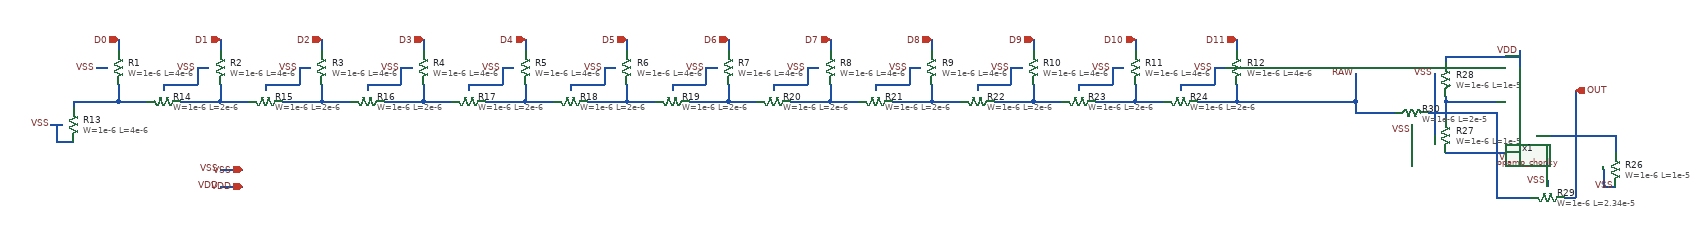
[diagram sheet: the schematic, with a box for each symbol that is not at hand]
v {xschem version=3.4.8RC file_version=1.3}
G {}
K {}
V {}
S {}
F {}
E {}
N -1370 -20 -1350 -20 {lab=VSS}
N -1190 -20 -1170 -20 {lab=VSS}
N -1010 -20 -990 -20 {lab=VSS}
N -830 -20 -810 -20 {lab=VSS}
N -650 -20 -630 -20 {lab=VSS}
N -470 -20 -450 -20 {lab=VSS}
N -290 -20 -270 -20 {lab=VSS}
N -110 -20 -90 -20 {lab=VSS}
N 70 -20 90 -20 {lab=VSS}
N 250 -20 270 -20 {lab=VSS}
N 430 -20 450 -20 {lab=VSS}
N 610 -20 630 -20 {lab=VSS}
N -1330 -70 -1330 -50 {lab=D0}
N -1150 -70 -1150 -50 {lab=D1}
N -970 -70 -970 -50 {lab=D2}
N -790 -70 -790 -50 {lab=D3}
N -610 -70 -610 -50 {lab=D4}
N -430 -70 -430 -50 {lab=D5}
N -250 -70 -250 -50 {lab=D6}
N -70 -70 -70 -50 {lab=D7}
N 110 -70 110 -50 {lab=D8}
N 290 -70 290 -50 {lab=D9}
N 470 -70 470 -50 {lab=D10}
N 650 -70 650 -50 {lab=D11}
N -1450 80 -1430 80 {lab=VSS}
N -1440 110 -1410 110 {lab=VSS}
N -1440 80 -1440 110 {lab=VSS}
N -1250 10 -1250 20 {lab=VSS}
N -1250 10 -1190 10 {lab=VSS}
N -1190 -20 -1190 10 {lab=VSS}
N -1330 10 -1330 40 {lab=#net1}
N -1330 40 -1280 40 {lab=#net1}
N -1220 40 -1150 40 {lab=#net2}
N -1150 10 -1150 40 {lab=#net2}
N -1150 40 -1100 40 {lab=#net2}
N -1040 40 -970 40 {lab=#net3}
N -970 10 -970 40 {lab=#net3}
N -1070 10 -1070 20 {lab=VSS}
N -1070 10 -1010 10 {lab=VSS}
N -1010 -20 -1010 10 {lab=VSS}
N -970 40 -920 40 {lab=#net3}
N -860 40 -790 40 {lab=#net4}
N -790 10 -790 40 {lab=#net4}
N -890 10 -890 20 {lab=VSS}
N -890 10 -830 10 {lab=VSS}
N -830 -20 -830 10 {lab=VSS}
N -1410 40 -1410 50 {lab=#net1}
N -1410 40 -1330 40 {lab=#net1}
N -790 40 -740 40 {lab=#net4}
N -680 40 -610 40 {lab=#net5}
N -610 10 -610 40 {lab=#net5}
N -710 10 -710 20 {lab=VSS}
N -710 10 -650 10 {lab=VSS}
N -650 -20 -650 10 {lab=VSS}
N -610 40 -560 40 {lab=#net5}
N -530 10 -530 20 {lab=VSS}
N -530 10 -470 10 {lab=VSS}
N -470 -20 -470 10 {lab=VSS}
N -500 40 -430 40 {lab=#net6}
N -430 10 -430 40 {lab=#net6}
N -430 40 -380 40 {lab=#net6}
N -320 40 -250 40 {lab=#net7}
N -250 10 -250 40 {lab=#net7}
N -350 10 -350 20 {lab=VSS}
N -350 10 -290 10 {lab=VSS}
N -290 -20 -290 10 {lab=VSS}
N -250 40 -200 40 {lab=#net7}
N -170 10 -170 20 {lab=VSS}
N -170 10 -110 10 {lab=VSS}
N -110 -20 -110 10 {lab=VSS}
N -140 40 -70 40 {lab=#net8}
N -70 10 -70 40 {lab=#net8}
N -70 40 -20 40 {lab=#net8}
N 10 10 10 20 {lab=VSS}
N 10 10 70 10 {lab=VSS}
N 70 -20 70 10 {lab=VSS}
N 40 40 110 40 {lab=#net9}
N 110 10 110 40 {lab=#net9}
N 110 40 160 40 {lab=#net9}
N 190 10 190 20 {lab=VSS}
N 190 10 250 10 {lab=VSS}
N 250 -20 250 10 {lab=VSS}
N 220 40 290 40 {lab=#net10}
N 290 10 290 40 {lab=#net10}
N 290 40 340 40 {lab=#net10}
N 370 10 370 20 {lab=VSS}
N 370 10 430 10 {lab=VSS}
N 430 -20 430 10 {lab=VSS}
N 400 40 470 40 {lab=#net11}
N 470 10 470 40 {lab=#net11}
N 470 40 520 40 {lab=#net11}
N 550 10 550 20 {lab=VSS}
N 550 10 610 10 {lab=VSS}
N 610 -20 610 10 {lab=VSS}
N 580 40 650 40 {lab=RAW}
N 650 10 650 40 {lab=RAW}
N -1150 160 -1110 160 {lab=VSS}
N -1150 190 -1110 190 {lab=VDD}
N 650 40 760 40 {lab=RAW}
N 760 40 820 40 {lab=RAW}
N 860 -10 860 40 {lab=RAW}
N 820 40 860 40 {lab=RAW}
N 1150 -50 1150 -20 {lab=VDD}
N 1150 120 1150 140 {lab=VSS}
N 1250 50 1250 210 {lab=OUT}
N 1180 100 1320 100 {lab=#net12}
N 1320 100 1320 130 {lab=#net12}
N 1300 160 1300 190 {lab=VSS}
N 1300 190 1320 190 {lab=VSS}
N 1250 20 1250 50 {lab=OUT}
N 1020 40 1110 40 {lab=#net13}
N 1020 30 1020 40 {lab=#net13}
N 1020 -40 1020 -30 {lab=VDD}
N 1020 -40 1150 -40 {lab=VDD}
N 1020 40 1020 70 {lab=#net13}
N 1020 130 1150 130 {lab=VSS}
N 1000 -0 1000 100 {lab=VSS}
N 1230 210 1250 210 {lab=OUT}
N 1110 210 1170 210 {lab=#net14}
N 1110 60 1110 210 {lab=#net14}
N 990 60 1110 60 {lab=#net14}
N 860 60 930 60 {lab=RAW}
N 860 40 860 60 {lab=RAW}
N 1200 180 1200 190 {lab=VSS}
N 1000 -10 1000 -0 {lab=VSS}
N 960 80 960 90 {lab=VSS}
C {lab_pin.sym} -1370 -20 0 0 {name=p1 sig_type=std_logic lab=VSS}
C {lab_pin.sym} -1190 -20 0 0 {name=p2 sig_type=std_logic lab=VSS}
C {lab_pin.sym} -1010 -20 0 0 {name=p3 sig_type=std_logic lab=VSS}
C {lab_pin.sym} -830 -20 0 0 {name=p4 sig_type=std_logic lab=VSS}
C {lab_pin.sym} -650 -20 0 0 {name=p5 sig_type=std_logic lab=VSS}
C {lab_pin.sym} -470 -20 0 0 {name=p6 sig_type=std_logic lab=VSS}
C {lab_pin.sym} -290 -20 0 0 {name=p7 sig_type=std_logic lab=VSS}
C {lab_pin.sym} -110 -20 0 0 {name=p8 sig_type=std_logic lab=VSS}
C {lab_pin.sym} 70 -20 0 0 {name=p9 sig_type=std_logic lab=VSS}
C {lab_pin.sym} 250 -20 0 0 {name=p10 sig_type=std_logic lab=VSS}
C {lab_pin.sym} 430 -20 0 0 {name=p11 sig_type=std_logic lab=VSS}
C {lab_pin.sym} 610 -20 0 0 {name=p12 sig_type=std_logic lab=VSS}
C {ipin.sym} -1330 -70 1 0 {name=p13 lab=D0}
C {ipin.sym} -1150 -70 1 0 {name=p14 lab=D1}
C {ipin.sym} -970 -70 1 0 {name=p15 lab=D2}
C {ipin.sym} -790 -70 1 0 {name=p16 lab=D3}
C {ipin.sym} -610 -70 1 0 {name=p17 lab=D4}
C {ipin.sym} -430 -70 1 0 {name=p18 lab=D5}
C {ipin.sym} -250 -70 1 0 {name=p19 lab=D6}
C {ipin.sym} -70 -70 1 0 {name=p20 lab=D7}
C {ipin.sym} 110 -70 1 0 {name=p21 lab=D8}
C {ipin.sym} 290 -70 1 0 {name=p22 lab=D9}
C {ipin.sym} 470 -70 1 0 {name=p23 lab=D10}
C {ipin.sym} 650 -70 1 0 {name=p24 lab=D11}
C {lab_pin.sym} -1450 80 0 0 {name=p25 sig_type=std_logic lab=VSS}
C {lab_pin.sym} -1150 160 0 0 {name=p26 sig_type=std_logic lab=VSS}
C {iopin.sym} -1110 160 0 0 {name=p27 lab=VSS}
C {lab_pin.sym} -1150 190 0 0 {name=p30 sig_type=std_logic lab=VDD}
C {iopin.sym} -1110 190 0 0 {name=p31 lab=VDD}
C {lab_pin.sym} 860 -10 1 0 {name=p28 sig_type=std_logic lab=RAW}
C {lab_pin.sym} 1150 -50 1 0 {name=p29 sig_type=std_logic lab=VDD}
C {lab_pin.sym} 1150 140 3 0 {name=p32 sig_type=std_logic lab=VSS}
C {symbols/npolyf_u.sym} 1320 160 0 0 {name=R26
W=1e-6
L=1e-5
model=ppolyf_u_1k_6p0
spiceprefix=X
m=1}
C {opin.sym} 1250 20 0 0 {name=p33 lab=OUT}
C {symbols/npolyf_u.sym} 1020 100 0 0 {name=R27
W=1e-6
L=1e-5
model=ppolyf_u_1k_6p0
spiceprefix=X
m=1}
C {symbols/npolyf_u.sym} 1020 0 0 0 {name=R28
W=1e-6
L=1e-5
model=ppolyf_u_1k_6p0
spiceprefix=X
m=1}
C {symbols/ppolyf_u_1k_6p0.sym} -1330 -20 0 0 {name=R1
W=1e-6
L=4e-6
model=ppolyf_u_1k_6p0
spiceprefix=X
m=1}
C {symbols/ppolyf_u_1k_6p0.sym} -1150 -20 0 0 {name=R2
W=1e-6
L=4e-6
model=ppolyf_u_1k_6p0
spiceprefix=X
m=1}
C {symbols/ppolyf_u_1k_6p0.sym} -970 -20 0 0 {name=R3
W=1e-6
L=4e-6
model=ppolyf_u_1k_6p0
spiceprefix=X
m=1}
C {symbols/ppolyf_u_1k_6p0.sym} -790 -20 0 0 {name=R4
W=1e-6
L=4e-6
model=ppolyf_u_1k_6p0
spiceprefix=X
m=1}
C {symbols/ppolyf_u_1k_6p0.sym} -610 -20 0 0 {name=R5
W=1e-6
L=4e-6
model=ppolyf_u_1k_6p0
spiceprefix=X
m=1}
C {symbols/ppolyf_u_1k_6p0.sym} -430 -20 0 0 {name=R6
W=1e-6
L=4e-6
model=ppolyf_u_1k_6p0
spiceprefix=X
m=1}
C {symbols/ppolyf_u_1k_6p0.sym} -250 -20 0 0 {name=R7
W=1e-6
L=4e-6
model=ppolyf_u_1k_6p0
spiceprefix=X
m=1}
C {symbols/ppolyf_u_1k_6p0.sym} -70 -20 0 0 {name=R8
W=1e-6
L=4e-6
model=ppolyf_u_1k_6p0
spiceprefix=X
m=1}
C {symbols/ppolyf_u_1k_6p0.sym} 110 -20 0 0 {name=R9
W=1e-6
L=4e-6
model=ppolyf_u_1k_6p0
spiceprefix=X
m=1}
C {symbols/ppolyf_u_1k_6p0.sym} 290 -20 0 0 {name=R10
W=1e-6
L=4e-6
model=ppolyf_u_1k_6p0
spiceprefix=X
m=1}
C {symbols/ppolyf_u_1k_6p0.sym} 470 -20 0 0 {name=R11
W=1e-6
L=4e-6
model=ppolyf_u_1k_6p0
spiceprefix=X
m=1}
C {symbols/ppolyf_u_1k_6p0.sym} 650 -20 0 0 {name=R12
W=1e-6
L=4e-6
model=ppolyf_u_1k_6p0
spiceprefix=X
m=1}
C {symbols/ppolyf_u_1k_6p0.sym} -1410 80 0 0 {name=R13
W=1e-6
L=4e-6
model=ppolyf_u_1k_6p0
spiceprefix=X
m=1}
C {symbols/ppolyf_u_1k_6p0.sym} -1250 40 1 0 {name=R14
W=1e-6
L=2e-6
model=ppolyf_u_1k_6p0
spiceprefix=X
m=1}
C {symbols/ppolyf_u_1k_6p0.sym} -1070 40 1 0 {name=R15
W=1e-6
L=2e-6
model=ppolyf_u_1k_6p0
spiceprefix=X
m=1}
C {symbols/ppolyf_u_1k_6p0.sym} -890 40 1 0 {name=R16
W=1e-6
L=2e-6
model=ppolyf_u_1k_6p0
spiceprefix=X
m=1}
C {symbols/ppolyf_u_1k_6p0.sym} -710 40 1 0 {name=R17
W=1e-6
L=2e-6
model=ppolyf_u_1k_6p0
spiceprefix=X
m=1}
C {symbols/ppolyf_u_1k_6p0.sym} -530 40 1 0 {name=R18
W=1e-6
L=2e-6
model=ppolyf_u_1k_6p0
spiceprefix=X
m=1}
C {symbols/ppolyf_u_1k_6p0.sym} -350 40 1 0 {name=R19
W=1e-6
L=2e-6
model=ppolyf_u_1k_6p0
spiceprefix=X
m=1}
C {symbols/ppolyf_u_1k_6p0.sym} -170 40 1 0 {name=R20
W=1e-6
L=2e-6
model=ppolyf_u_1k_6p0
spiceprefix=X
m=1}
C {symbols/ppolyf_u_1k_6p0.sym} 10 40 1 0 {name=R21
W=1e-6
L=2e-6
model=ppolyf_u_1k_6p0
spiceprefix=X
m=1}
C {symbols/ppolyf_u_1k_6p0.sym} 190 40 1 0 {name=R22
W=1e-6
L=2e-6
model=ppolyf_u_1k_6p0
spiceprefix=X
m=1}
C {symbols/ppolyf_u_1k_6p0.sym} 370 40 1 0 {name=R23
W=1e-6
L=2e-6
model=ppolyf_u_1k_6p0
spiceprefix=X
m=1}
C {symbols/ppolyf_u_1k_6p0.sym} 550 40 1 0 {name=R24
W=1e-6
L=2e-6
model=ppolyf_u_1k_6p0
spiceprefix=X
m=1}
C {symbols/ppolyf_u_1k_6p0.sym} 960 60 3 0 {name=R30
W=1e-6
L=2e-5
model=ppolyf_u_1k_6p0
spiceprefix=X
m=1}
C {symbols/ppolyf_u_1k_6p0.sym} 1200 210 1 0 {name=R29
W=1e-6
L=2.34e-5
model=ppolyf_u_1k_6p0
spiceprefix=X
m=1}
C {opamp_chonky.sym} 1260 50 0 0 {name=x1}
C {lab_pin.sym} 1320 190 3 0 {name=p34 sig_type=std_logic lab=VSS}
C {lab_pin.sym} 1200 180 1 0 {name=p35 sig_type=std_logic lab=VSS}
C {lab_pin.sym} 1000 -10 1 0 {name=p36 sig_type=std_logic lab=VSS}
C {lab_pin.sym} 960 90 3 0 {name=p37 sig_type=std_logic lab=VSS}
